VERSION 5.7 ;
BUSBITCHARS "[]" ;
DIVIDERCHAR "/" ;

PROPERTYDEFINITIONS
  MACRO CatenaDesignType STRING ;
  LAYER LEF58_TYPE STRING ;
  LAYER LEF58_ENCLOSURE STRING ;
  LAYER LEF58_SPACING STRING ;
  LAYER LEF58_WIDTH STRING ;
END PROPERTYDEFINITIONS

UNITS
  DATABASE MICRONS 1000 ;
END UNITS
MANUFACTURINGGRID 0.005 ;
LAYER OVERLAP
  TYPE OVERLAP ;
END OVERLAP

LAYER pwell
  TYPE MASTERSLICE ;
  PROPERTY LEF58_TYPE "TYPE PWELL ;" ;
END pwell

LAYER nwell
  TYPE MASTERSLICE ;
  PROPERTY LEF58_TYPE "TYPE NWELL ;" ;
  PROPERTY LEF58_SPACING "SPACING 1.27 ;" ;
  PROPERTY LEF58_WIDTH "WIDTH 0.84 ;" ;
END nwell

LAYER diff
  TYPE MASTERSLICE ;
  PROPERTY LEF58_TYPE "TYPE DIFFUSION ;" ;
END diff

LAYER tap
  TYPE MASTERSLICE ;
  PROPERTY LEF58_TYPE "TYPE DIFFUSION ;" ;
END tap

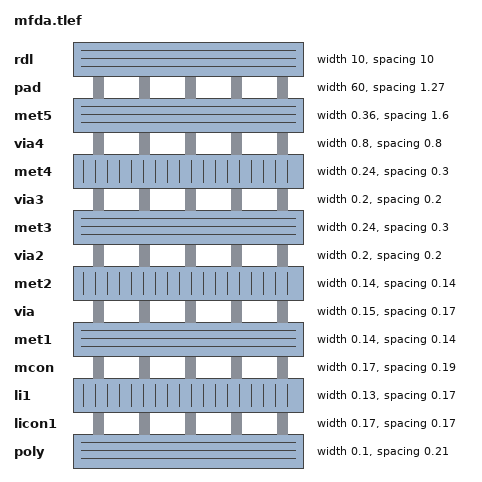
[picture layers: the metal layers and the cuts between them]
LAYER poly
  TYPE ROUTING ;
  DIRECTION HORIZONTAL ;
  WIDTH 0.1 ;
  SPACING 0.21 ;
  MINWIDTH 0.15 ;
  ANTENNAMODEL OXIDE1 ;
  PROPERTY LEF58_TYPE "TYPE POLYROUTING ;" ;
END poly

LAYER licon1
  TYPE CUT ;
  SPACING 0.17 ;
  WIDTH 0.17 ;
  ANTENNAMODEL OXIDE1 ;
END licon1

LAYER li1
  TYPE ROUTING ;
  DIRECTION VERTICAL ;
  WIDTH 0.13 ;
  SPACING 0.17 ;
  MINWIDTH 0.17 ;
  ANTENNAMODEL OXIDE1 ;
    ANTENNASIDEAREARATIO 75 ;
    ANTENNADIFFSIDEAREARATIO PWL ( ( 0 75 ) ( 0.0125 75 ) ( 0.0225 85.125 ) ( 22.5 10200 ) ) ;
END li1

LAYER mcon
  TYPE CUT ;
  SPACING 0.19 ;
  WIDTH 0.17 ;
  ANTENNAMODEL OXIDE1 ;
    ANTENNAAREARATIO 3 ;
    ANTENNADIFFAREARATIO PWL ( ( 0 3 ) ( 0.0125 3 ) ( 0.0225 3.405 ) ( 22.5 408 ) ) ;
END mcon

LAYER met1
  TYPE ROUTING ;
  DIRECTION HORIZONTAL ;
  WIDTH 0.14 ;
  OFFSET 0.185 0.185 ;
  AREA 0.083 ;
  SPACING 0.14 ;
  SPACING 0.28 RANGE 3.005 10000 ;
  SPACING 0.28 RANGE 3.005 10000 INFLUENCE 0.28 ;
  MINENCLOSEDAREA 0.14 ;
  ANTENNAMODEL OXIDE1 ;
    ANTENNASIDEAREARATIO 400 ;
    ANTENNADIFFSIDEAREARATIO PWL ( ( 0 400 ) ( 0.0125 400 ) ( 0.0225 2609 ) ( 22.5 11600 ) ) ;
END met1

LAYER via
  TYPE CUT ;
  SPACING 0.17 ;
  WIDTH 0.15 ;
  ANTENNAMODEL OXIDE1 ;
    ANTENNAAREARATIO 6 ;
    ANTENNADIFFAREARATIO PWL ( ( 0 6 ) ( 0.0125 6 ) ( 0.0225 6.81 ) ( 22.5 816 ) ) ;
END via

LAYER met2
  TYPE ROUTING ;
  DIRECTION VERTICAL ;
  WIDTH 0.14 ;
  OFFSET 0.185 0.185 ;
  AREA 0.0676 ;
  SPACING 0.14 ;
  SPACING 0.28 RANGE 3.005 10000 ;
  SPACING 0.28 RANGE 3.005 10000 INFLUENCE 0.28 ;
  MINENCLOSEDAREA 0.14 ;
  ANTENNAMODEL OXIDE1 ;
    ANTENNASIDEAREARATIO 400 ;
    ANTENNADIFFSIDEAREARATIO PWL ( ( 0 400 ) ( 0.0125 400 ) ( 0.0225 2609 ) ( 22.5 11600 ) ) ;
END met2

LAYER via2
  TYPE CUT ;
  SPACING 0.2 ;
  WIDTH 0.2 ;
  ANTENNAMODEL OXIDE1 ;
    ANTENNAAREARATIO 6 ;
    ANTENNADIFFAREARATIO PWL ( ( 0 6 ) ( 0.0125 6 ) ( 0.0225 6.81 ) ( 22.5 816 ) ) ;
END via2

LAYER met3
  TYPE ROUTING ;
  DIRECTION HORIZONTAL ;
  WIDTH 0.24 ;
  OFFSET 0.305 0.305 ;
  AREA 0.24 ;
  SPACING 0.3 ;
  SPACING 0.4 RANGE 3.005 10000 ;
  SPACING 0.4 RANGE 3.005 10000 INFLUENCE 0.4 ;
  MINWIDTH 0.3 ;
  ANTENNAMODEL OXIDE1 ;
    ANTENNASIDEAREARATIO 400 ;
    ANTENNADIFFSIDEAREARATIO PWL ( ( 0 400 ) ( 0.0125 400 ) ( 0.0225 2609 ) ( 22.5 11600 ) ) ;
END met3

LAYER via3
  TYPE CUT ;
  SPACING 0.2 ;
  WIDTH 0.2 ;
  ANTENNAMODEL OXIDE1 ;
    ANTENNAAREARATIO 6 ;
    ANTENNADIFFAREARATIO PWL ( ( 0 6 ) ( 0.0125 6 ) ( 0.0225 6.81 ) ( 22.5 816 ) ) ;
END via3

LAYER met4
  TYPE ROUTING ;
  DIRECTION VERTICAL ;
  WIDTH 0.24 ;
  OFFSET 0.305 0.305 ;
  AREA 0.24 ;
  SPACING 0.3 ;
  SPACING 0.4 RANGE 3.005 10000 ;
  SPACING 0.4 RANGE 3.005 10000 INFLUENCE 0.4 ;
  MINWIDTH 0.3 ;
  ANTENNAMODEL OXIDE1 ;
    ANTENNASIDEAREARATIO 400 ;
    ANTENNADIFFSIDEAREARATIO PWL ( ( 0 400 ) ( 0.0125 400 ) ( 0.0225 2609 ) ( 22.5 11600 ) ) ;
END met4

LAYER via4
  TYPE CUT ;
  SPACING 0.8 ;
  WIDTH 0.8 ;
  ANTENNAMODEL OXIDE1 ;
    ANTENNAAREARATIO 6 ;
    ANTENNADIFFAREARATIO PWL ( ( 0 6 ) ( 0.0125 6 ) ( 0.0225 6.81 ) ( 22.5 816 ) ) ;
END via4

LAYER met5
  TYPE ROUTING ;
  DIRECTION HORIZONTAL ;
  WIDTH 0.36 ;
  OFFSET 1.555 1.555 ;
  SPACING 1.6 ;
  MINWIDTH 1.6 ;
  ANTENNAMODEL OXIDE1 ;
    ANTENNASIDEAREARATIO 400 ;
    ANTENNADIFFSIDEAREARATIO PWL ( ( 0 400 ) ( 0.0125 400 ) ( 0.0225 2609 ) ( 22.5 11600 ) ) ;
END met5

LAYER pad
  TYPE CUT ;
  SPACING 1.27 ;
  WIDTH 60 ;
  ANTENNAMODEL OXIDE1 ;
END pad

LAYER rdl
  TYPE ROUTING ;
  DIRECTION HORIZONTAL ;
  WIDTH 10 ;
  SPACING 10 ;
  ANTENNAMODEL OXIDE1 ;
END rdl

VIARULE M4M5_C GENERATE DEFAULT
  LAYER met5 ;
    ENCLOSURE 0.31 0.31 ;
  LAYER met4 ;
    ENCLOSURE 0.19 0.19 ;
  LAYER via4 ;
    RECT -0.4 -0.4 0.4 0.4 ;
    SPACING 0 BY 0 ;
    RESISTANCE 0.380000 ;
END M4M5_C

VIARULE M3M4_C GENERATE DEFAULT
  LAYER met4 ;
    ENCLOSURE 0.065 0.065 ;
  LAYER met3 ;
    ENCLOSURE 0.09 0.09 ;
  LAYER via3 ;
    RECT -0.1 -0.1 0.1 0.1 ;
    SPACING 0 BY 0 ;
    RESISTANCE 3.410000 ;
END M3M4_C

VIARULE M2M3_C GENERATE DEFAULT
  LAYER met3 ;
    ENCLOSURE 0.065 0.065 ;
  LAYER met2 ;
    ENCLOSURE 0.085 0.085 ;
  LAYER via2 ;
    RECT -0.1 -0.1 0.1 0.1 ;
    SPACING 0 BY 0 ;
    RESISTANCE 3.410000 ;
END M2M3_C

VIARULE M1M2_C GENERATE DEFAULT
  LAYER met2 ;
    ENCLOSURE 0.085 0.085 ;
  LAYER met1 ;
    ENCLOSURE 0.085 0.085 ;
  LAYER via ;
    RECT -0.075 -0.075 0.075 0.075 ;
    SPACING 0 BY 0 ;
    RESISTANCE 4.500000 ;
END M1M2_C

VIARULE L1M1_C GENERATE DEFAULT
  LAYER met1 ;
    ENCLOSURE 0.06 0.06 ;
  LAYER li1 ;
    ENCLOSURE 0 0 ;
  LAYER mcon ;
    RECT -0.085 -0.085 0.085 0.085 ;
    SPACING 0 BY 0 ;
    RESISTANCE 9.300000 ;
END L1M1_C

VIARULE PYL1_C GENERATE DEFAULT
  LAYER poly ;
    ENCLOSURE 0.08 0.08 ;
  LAYER li1 ;
    ENCLOSURE 0.08 0.08 ;
  LAYER licon1 ;
    RECT -0.085 -0.085 0.085 0.085 ;
    SPACING 0 BY 0 ;
    RESISTANCE 145.279999 ;
END PYL1_C

VIARULE TPL1_C GENERATE DEFAULT
  LAYER li1 ;
    ENCLOSURE 0.08 0.08 ;
  LAYER tap ;
    ENCLOSURE 0.12 0.12 ;
  LAYER licon1 ;
    RECT -0.085 -0.085 0.085 0.085 ;
    SPACING 0 BY 0 ;
    RESISTANCE 600.000000 ;
END TPL1_C

SITE CoreSite
  CLASS CORE ;
  SYMMETRY Y ;
  SIZE 84 BY 60 ;
END CoreSite

END LIBRARY
